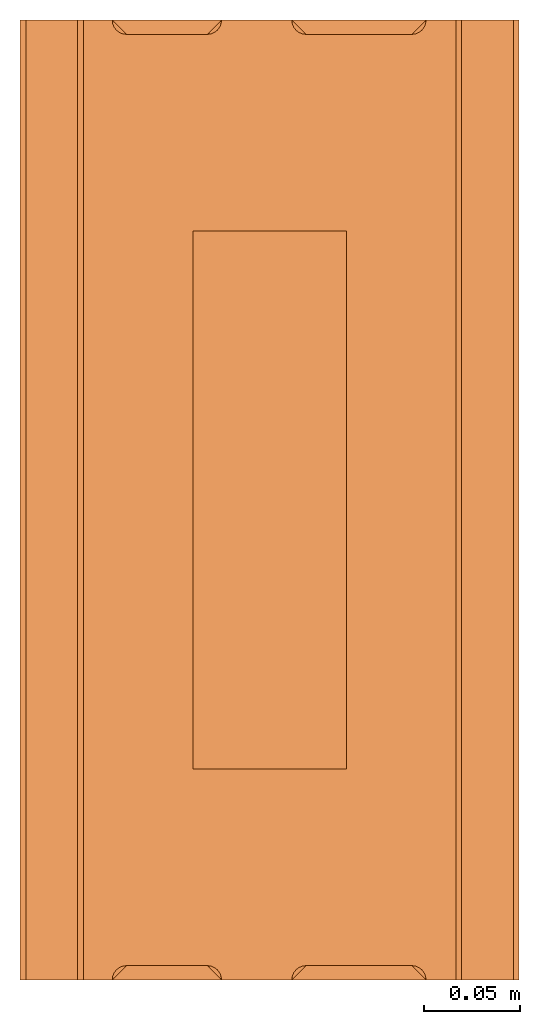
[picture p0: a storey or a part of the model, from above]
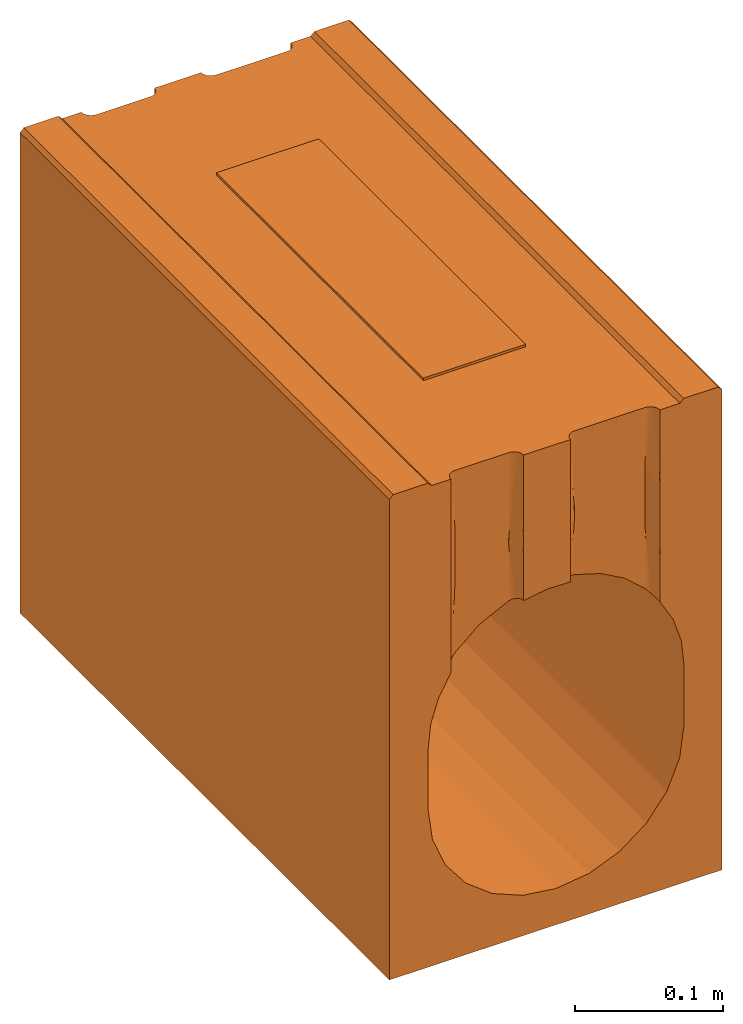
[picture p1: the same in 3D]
Properties of the parts of a building model (IFC2X3)

# File
Description: ViewDefinition [CoordinationView]
File name: 33103 - PD 200 F 10.3 Rodding Access 500mm LG.ifc
Time: 2013-10-11T12:56:10
Written by: Autodesk Revit 2013
Made in: 20120221_2030(x64)

# IfcProject, Project Number
LongName: Project Name; Phase: Project Status

# IfcSite, Default
RefLatitude: 42, 21, 30, 344238; RefLongitude: -71, -3, -35, -194702; RefElevation: 0 mm

# IfcBuilding
Pset_BuildingCommon - NumberOfStoreys: 2
Other - Project Number: Project Number; Project Address: Enter address here; Client Name: Owner; Project Name: Project Name; Project Status: Project Status; Project Issue Date: Issue Date

# IfcBuildingStorey (2)
Graphics - Symbol at End 2 Default: yes; Symbol at End 1 Default: no; Symbol: M_Level Head - Circle: M_Level Head - Circle; Line Pattern: Center; Color: 0; Line Weight: 1
Constraints - Elevation Base: 0
Dimensions - Computation Height: 0 mm
Identity Data - Building Story: yes; Structural: no
Name | LongName = Name | Elevation (mm) = Constraints, Elevation (mm)
B.O. Footing | B.O. Footing | -4600
T.O. Footing | T.O. Footing | -4300

# IfcBuildingElementProxy: 33103 - PD 200 F 10.3 Rodding Access 500mm LG, Civil-Drainage-Channel-ACO-RoadDrain 200:33103 - PD 200 F 10.3 Rodding Access 500mm LG:33103 - PD 200 F 10.3 Rodding Access 500mm LG:309971
In: B.O. Footing
Material: Acetal Resin, Black
Other - Revision: 1; CreatedBy: www.aco.co.uk
Green Building Properties - Access Cover/Frame Recyclable: Fully recyclable; Channel Recycled Material Content: 20% minimum; End Cap Recycled Material Content: N/A; Channel Recyclable: Fully recyclable; End Cap Recyclable: N/A; Access Cover/Frame Recycled Material Content: Between 40% - 90%
Constraints - Level: Level: T.O. Footing; Moves With Nearby Elements: no
Dimensions - Volume: 30640649 mm3; Custom Void Length: 0 mm; Length: 500 mm; Straight Void Length: 500 mm; Straight Void Start: 0 mm; I/O End Cap Void: 3500 mm; Pipe Depth: 6000 mm; Void Depth: -400 mm; Total Depth: 400 mm; Invert Depth.: 270 mm
Phasing - Phase Created: Phase 1
Pset_BuildingElementProxyCommon - Reference: 33103 - PD 200 F 10.3 Rodding Access 500mm LG
Data - Hydraulic Performance: http://www.aco.co.uk/download.php?id=256; Installation - Concrete Grade: Refer to brochure; ACO Hydraulic Design Software: http://www.acodesign.co.uk; Concrete Surround Volume - Load Class F 900 - Concrete Pavement: 0.29m³/m; Channel C.S.A: 0.41m²; Product Standard: BS EN 1433:2002, CE marked, Kitemarked; Product Dimensions: 500mm x 260mm x 400mm (LxWxH); Invert Depth: 370mm; Product Weight: 53.5 Kg; Connection Pipe O.D: N/A; Load Class: A 15 - F 900
Identity Data - Assembly Description: Rain Water Drainage; Cost: 0; Fax: +44 (0)1462 815895; Price: POA - contact ACO; Product Page URL: http://www.aco.co.uk/product_detail.php?id=21; URL: www.aco.co.uk; OmniClass Number: 23.70.50.24; Maintenance guidelines: http://www.aco.co.uk/download.php?id=256; Assembly Code: D2040; Product brochure: http://www.aco.co.uk/download.php?id=256; e-mail Sales: customersupport@aco.co.uk; Watermarked With: BIM Manager Premium Suite; Installation guidelines: http://www.aco.co.uk/download.php?id=256; Watermark 2: This file is water marked and users are prohibited to reproduce, adapt, distribute this information; Telephone: +44 (0)1462 816666; Product Code: 33103; Watermark 1: This file is the property of ACO Technologies PLC; e-mail Technical: technical@aco.co.uk; Model: ACO RoadDrain 200 PD200F; Address: ACO Business Park, Hitchin Road, Shefford, Bedfordshire, United Kingdom SG17 5TE; OmniClass Title: Rainwater Removal; Watermarked By: www.aco.co.uk; Manufacturer: ACO Technologies plc - ACO Water Management Division; Model Description: Monolithic Channel drainage system; Type Comments: ACO RoadDrain 200 PD200F 10.3 Constant Depth Access Channel 500mm Long
Construction - Channel 260mm Wide: no; Access unit: yes; Inlet Outlet end cap: no; Closing End Cap: no
General - TagNumber: 0.000000; SerialNumber: 0.000000
Materials and Finishes - Grating Material: N/A; Grating Finish: N/A; Grating Colour: N/A; Connection Pipe Colour: N/A; Connection Pipe Material: N/A; Access Cover/Frame Finish: Water Based Paint Coating; Access Cover/Frame Material: Ductile Iron; Channel Material: Vienite® Synthetic Resin Concrete; End Cap Colour: N/A; Channel Colour: Black; Access Cover/Frame Colour: Black; End Cap Material: N/A

# IfcOpeningElement: Recess (2)
In: T.O. Footing
Dimensions - Area: 26010000 mm2; Volume: 40263500000 mm3; Perimeter: 20400 mm; Thickness: 1550 mm
Structural - Structural: no; Enable Analytical Model: no
Constraints - Level: Level: T.O. Footing; Related to Mass: no; Room Bounding: yes; Height Offset From Level: 0 mm
Phasing - Phase Created: Phase 1
Analytical Properties - Thermal Resistance (R): 1.79211; Heat Transfer Coefficient (U): 0.558; Roughness: 1; Thermal mass: 2039700; Absorptance: 0.1
Graphics - Coarse Scale Fill Color: 0
Construction - Default Thickness: 1550 mm; Function: 0
Materials and Finishes - Structural Material: Grass

# IfcSlab: Floor:Generic Floor - 400mm, Floor:Generic Floor - 400mm:136436
In: T.O. Footing
PredefinedType: FLOOR; Material: Grass 50 mm, Earth 1500 mm
Dimensions - Area: 26010000 mm2; Volume: 40263500000 mm3; Perimeter: 20400 mm; Thickness: 1550 mm
Structural - Structural: no; Enable Analytical Model: no
Constraints - Level: Level: T.O. Footing; Related to Mass: no; Room Bounding: yes; Height Offset From Level: 0 mm
Phasing - Phase Created: Phase 1
Pset_SlabCommon - Reference: Generic Floor - 400mm; IsExternal: no; LoadBearing: yes
Analytical Properties - Thermal Resistance (R): 1.79211; Heat Transfer Coefficient (U): 0.558; Roughness: 1; Thermal mass: 2039700; Absorptance: 0.1
Graphics - Coarse Scale Fill Color: 0
Construction - Default Thickness: 1550 mm; Function: 0
Materials and Finishes - Structural Material: Grass
